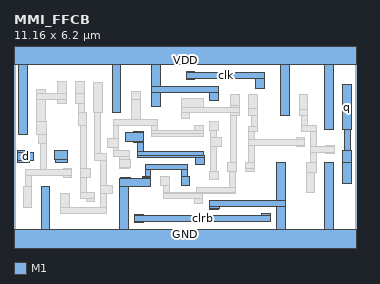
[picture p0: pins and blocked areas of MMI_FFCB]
MACRO MMI_FFCB
	CLASS CORE ;
	FOREIGN MMI_FFCB 0 0 ;
	SIZE 11.16 BY 6.2 ;
	SYMMETRY X Y ;
	SITE CORE1 ;
	PIN d
		DIRECTION input ;
		USE SIGNAL ;
		PORT
			LAYER M1 ;
			RECT 0.12 2.925 0.5 2.98 ;
			LAYER M1 ;
			RECT 0.12 2.645 0.635 2.925 ;
			LAYER M1 ;
			RECT 0.12 2.6 0.5 2.645 ;
		END
		AntennaGateArea 0.3465 ;
	END d
	PIN GND
		DIRECTION inout ;
		USE GROUND ;
		PORT
			LAYER M1 ;
			RECT 4.275 2.355 5.655 2.545 ;
			LAYER M1 ;
			RECT 4.275 2.145 4.465 2.355 ;
			LAYER M1 ;
			RECT 5.46 2.145 5.655 2.355 ;
			LAYER M1 ;
			RECT 4.19 2.11 4.47 2.145 ;
			LAYER M1 ;
			RECT 3.485 2.085 3.8 2.11 ;
			LAYER M1 ;
			RECT 4.185 2.085 4.47 2.11 ;
			LAYER M1 ;
			RECT 0.885 0.42 1.165 1.82 ;
			LAYER M1 ;
			RECT 3.45 1.8 4.47 2.085 ;
			LAYER M1 ;
			RECT 5.46 1.83 5.74 2.145 ;
			LAYER M1 ;
			RECT 3.45 0.42 3.73 1.8 ;
			LAYER M1 ;
			RECT 6.38 1.345 6.66 1.35 ;
			LAYER M1 ;
			RECT 8.57 1.345 8.85 2.595 ;
			LAYER M1 ;
			RECT 6.38 1.15 8.85 1.345 ;
			LAYER M1 ;
			RECT 6.38 1.1 6.695 1.15 ;
			LAYER M1 ;
			RECT 6.38 1.07 6.66 1.1 ;
			LAYER M1 ;
			RECT 8.57 0.42 8.85 1.15 ;
			LAYER M1 ;
			RECT 10.13 0.42 10.41 2.6 ;
			LAYER M1 ;
			RECT 0 -0.42 11.16 0.42 ;
		END
	END GND
	PIN q
		DIRECTION output ;
		USE SIGNAL ;
		PORT
			LAYER M1 ;
			RECT 10.72 3.66 11 5.13 ;
			LAYER M1 ;
			RECT 10.775 2.98 10.97 3.66 ;
			LAYER M1 ;
			RECT 10.725 2.6 11.01 2.98 ;
			LAYER M1 ;
			RECT 10.72 1.9 11 2.6 ;
		END
		AntennaDiffArea 0.91245 ;
	END q
	PIN VDD
		DIRECTION inout ;
		USE POWER ;
		PORT
			LAYER M1 ;
			RECT 0 5.78 11.16 6.62 ;
			LAYER M1 ;
			RECT 0.16 3.515 0.44 5.78 ;
			LAYER M1 ;
			RECT 3.2 4.22 3.48 5.78 ;
			LAYER M1 ;
			RECT 4.49 5.085 4.77 5.78 ;
			LAYER M1 ;
			RECT 4.49 4.89 6.665 5.085 ;
			LAYER M1 ;
			RECT 4.49 4.415 4.77 4.89 ;
			LAYER M1 ;
			RECT 6.38 4.605 6.665 4.89 ;
			LAYER M1 ;
			RECT 8.71 4.115 8.99 5.78 ;
			LAYER M1 ;
			RECT 10.13 3.66 10.41 5.78 ;
		END
	END VDD
	PIN clk
		DIRECTION input ;
		USE CLOCK ;
		PORT
			LAYER M1 ;
			RECT 5.625 5.54 5.905 5.575 ;
			LAYER M1 ;
			RECT 5.625 5.345 8.18 5.54 ;
			LAYER M1 ;
			RECT 5.625 5.295 5.905 5.345 ;
			LAYER M1 ;
			RECT 7.895 5.015 8.18 5.345 ;
			LAYER M1 ;
			RECT 3.89 3.565 4.225 3.6 ;
			LAYER M1 ;
			RECT 3.645 3.285 4.225 3.565 ;
			LAYER M1 ;
			RECT 3.89 3.25 4.225 3.285 ;
			LAYER M1 ;
			RECT 4.03 2.94 4.225 3.25 ;
			LAYER M1 ;
			RECT 4.03 2.825 6.19 2.94 ;
			LAYER M1 ;
			RECT 4.03 2.75 6.215 2.825 ;
			LAYER M1 ;
			RECT 5.935 2.545 6.215 2.75 ;
		END
		AntennaGateArea 0.44625 ;
	END clk
	PIN clrb
		DIRECTION input ;
		USE SIGNAL ;
		PORT
			LAYER M1 ;
			RECT 1.36 2.975 1.74 2.98 ;
			LAYER M1 ;
			RECT 1.325 2.695 1.74 2.975 ;
			LAYER M1 ;
			RECT 1.36 2.6 1.74 2.695 ;
			LAYER M1 ;
			RECT 3.935 0.865 4.215 0.91 ;
			LAYER M1 ;
			RECT 8.09 0.865 8.37 0.935 ;
			LAYER M1 ;
			RECT 3.935 0.67 8.37 0.865 ;
			LAYER M1 ;
			RECT 3.935 0.63 4.215 0.67 ;
			LAYER M1 ;
			RECT 8.09 0.655 8.37 0.67 ;
		END
		AntennaGateArea 0.5055 ;
	END clrb
	OBS
		LAYER M1 ;
		RECT 0.75 4.85 1.03 4.985 ;
		LAYER M1 ;
		RECT 1.42 4.85 1.7 5.235 ;
		LAYER M1 ;
		RECT 0.75 4.655 1.7 4.85 ;
		LAYER M1 ;
		RECT 0.75 3.925 1.03 4.655 ;
		LAYER M1 ;
		RECT 1.42 4.535 1.7 4.655 ;
		LAYER M1 ;
		RECT 2.01 4.83 2.29 5.235 ;
		LAYER M1 ;
		RECT 2.01 4.535 2.3 4.83 ;
		LAYER M1 ;
		RECT 2.11 4.23 2.3 4.535 ;
		LAYER M1 ;
		RECT 0.75 3.515 1.065 3.925 ;
		LAYER M1 ;
		RECT 2.11 3.805 2.365 4.23 ;
		LAYER M1 ;
		RECT 2.61 4.22 2.89 5.19 ;
		LAYER M1 ;
		RECT 3.84 4.655 4.12 4.915 ;
		LAYER M1 ;
		RECT 0.805 3.205 1.065 3.515 ;
		LAYER M1 ;
		RECT 0.87 2.355 1.065 3.205 ;
		LAYER M1 ;
		RECT 2.17 2.4 2.365 3.805 ;
		LAYER M1 ;
		RECT 2.64 2.885 2.83 4.22 ;
		LAYER M1 ;
		RECT 3.84 4.01 4.125 4.655 ;
		LAYER M1 ;
		RECT 5.9 4.685 6.18 4.69 ;
		LAYER M1 ;
		RECT 5.46 4.405 6.18 4.685 ;
		LAYER M1 ;
		RECT 7.07 4.445 7.35 4.815 ;
		LAYER M1 ;
		RECT 7.06 4.405 7.35 4.445 ;
		LAYER M1 ;
		RECT 5.46 4.21 7.35 4.405 ;
		LAYER M1 ;
		RECT 5.46 4.015 5.74 4.21 ;
		LAYER M1 ;
		RECT 7.06 4.115 7.35 4.21 ;
		LAYER M1 ;
		RECT 7.66 4.35 7.94 4.815 ;
		LAYER M1 ;
		RECT 7.66 4.115 7.95 4.35 ;
		LAYER M1 ;
		RECT 9.3 4.32 9.58 4.815 ;
		LAYER M1 ;
		RECT 9.3 4.115 9.585 4.32 ;
		LAYER M1 ;
		RECT 3.235 3.815 4.695 4.01 ;
		LAYER M1 ;
		RECT 3.235 3.365 3.425 3.815 ;
		LAYER M1 ;
		RECT 4.5 3.625 4.695 3.815 ;
		LAYER M1 ;
		RECT 5.905 3.625 6.185 3.815 ;
		LAYER M1 ;
		RECT 6.385 3.645 6.665 3.925 ;
		LAYER M1 ;
		RECT 3.04 3.085 3.425 3.365 ;
		LAYER M1 ;
		RECT 4.5 3.535 6.185 3.625 ;
		LAYER M1 ;
		RECT 4.5 3.43 6.18 3.535 ;
		LAYER M1 ;
		RECT 3.235 3 3.425 3.085 ;
		LAYER M1 ;
		RECT 2.64 2.675 3.025 2.885 ;
		LAYER M1 ;
		RECT 3.235 2.805 3.755 3 ;
		LAYER M1 ;
		RECT 1.61 2.355 1.89 2.4 ;
		LAYER M1 ;
		RECT 0.375 2.16 1.89 2.355 ;
		LAYER M1 ;
		RECT 0.375 1.82 0.57 2.16 ;
		LAYER M1 ;
		RECT 1.61 2.12 1.89 2.16 ;
		LAYER M1 ;
		RECT 2.17 2.12 2.48 2.4 ;
		LAYER M1 ;
		RECT 0.295 1.12 0.575 1.82 ;
		LAYER M1 ;
		RECT 2.17 1.625 2.365 2.12 ;
		LAYER M1 ;
		RECT 2.83 1.85 3.025 2.675 ;
		LAYER M1 ;
		RECT 3.435 2.7 3.755 2.805 ;
		LAYER M1 ;
		RECT 6.425 3.395 6.62 3.645 ;
		LAYER M1 ;
		RECT 6.425 3.115 6.755 3.395 ;
		LAYER M1 ;
		RECT 3.435 2.42 3.8 2.7 ;
		LAYER M1 ;
		RECT 3.435 2.405 3.755 2.42 ;
		LAYER M1 ;
		RECT 6.425 2.31 6.62 3.115 ;
		LAYER M1 ;
		RECT 7.06 2.59 7.255 4.115 ;
		LAYER M1 ;
		RECT 7.755 3.785 7.95 4.115 ;
		LAYER M1 ;
		RECT 7.665 3.59 7.95 3.785 ;
		LAYER M1 ;
		RECT 9.395 3.805 9.585 4.115 ;
		LAYER M1 ;
		RECT 9.395 3.61 9.88 3.805 ;
		LAYER M1 ;
		RECT 7.665 3.355 7.855 3.59 ;
		LAYER M1 ;
		RECT 9.205 3.355 9.485 3.4 ;
		LAYER M1 ;
		RECT 7.665 3.165 9.485 3.355 ;
		LAYER M1 ;
		RECT 7.665 2.59 7.855 3.165 ;
		LAYER M1 ;
		RECT 9.205 3.12 9.485 3.165 ;
		LAYER M1 ;
		RECT 9.685 3.13 9.88 3.61 ;
		LAYER M1 ;
		RECT 10.175 3.13 10.455 3.165 ;
		LAYER M1 ;
		RECT 9.685 2.935 10.455 3.13 ;
		LAYER M1 ;
		RECT 9.685 2.595 9.88 2.935 ;
		LAYER M1 ;
		RECT 10.175 2.885 10.455 2.935 ;
		LAYER M1 ;
		RECT 6.975 2.31 7.255 2.59 ;
		LAYER M1 ;
		RECT 7.565 2.39 7.855 2.59 ;
		LAYER M1 ;
		RECT 7.565 2.31 7.845 2.39 ;
		LAYER M1 ;
		RECT 2.17 1.61 2.54 1.625 ;
		LAYER M1 ;
		RECT 1.52 1.13 1.8 1.57 ;
		LAYER M1 ;
		RECT 2.17 1.435 2.63 1.61 ;
		LAYER M1 ;
		RECT 2.35 1.33 2.63 1.435 ;
		LAYER M1 ;
		RECT 2.83 1.57 3.23 1.85 ;
		LAYER M1 ;
		RECT 4.78 1.83 5.06 2.145 ;
		LAYER M1 ;
		RECT 6.38 2.03 6.66 2.31 ;
		LAYER M1 ;
		RECT 2.83 1.13 3.025 1.57 ;
		LAYER M1 ;
		RECT 1.52 0.94 3.025 1.13 ;
		LAYER M1 ;
		RECT 4.87 1.615 5.06 1.83 ;
		LAYER M1 ;
		RECT 7.04 1.79 7.23 2.31 ;
		LAYER M1 ;
		RECT 5.96 1.615 7.23 1.79 ;
		LAYER M1 ;
		RECT 4.87 1.595 7.23 1.615 ;
		LAYER M1 ;
		RECT 4.87 1.425 6.16 1.595 ;
		LAYER M1 ;
		RECT 5.88 1.265 6.16 1.425 ;
		LAYER M1 ;
		RECT 9.535 2.275 9.88 2.595 ;
		LAYER M1 ;
		RECT 9.535 1.625 9.815 2.275 ;
	END
END MMI_FFCB
